VERSION 5.7 ;
BUSBITCHARS "[]" ;
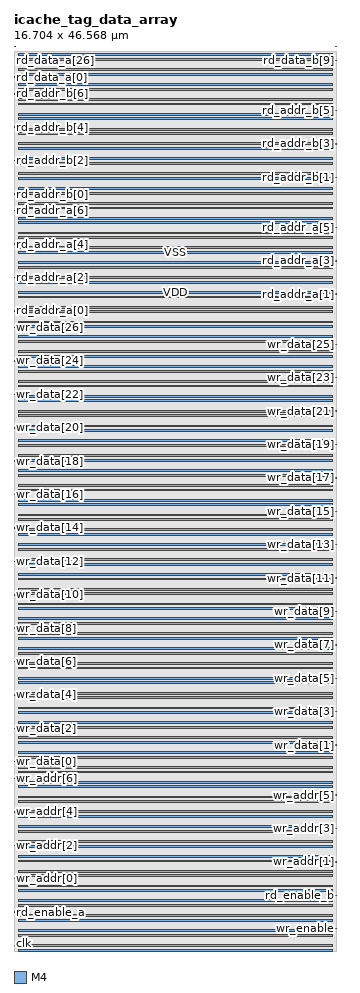
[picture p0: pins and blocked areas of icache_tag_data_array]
MACRO icache_tag_data_array
  FOREIGN icache_tag_data_array 0 0 ;
  SYMMETRY X Y R90 ;
  SIZE 16.704 BY 46.568 ;
  CLASS BLOCK ;
  PIN clk
    DIRECTION INPUT ;
    USE SIGNAL ;
    SHAPE ABUTMENT ;
    PORT
      LAYER M4 ;
      RECT 0.000 0.276 0.072 0.300 ;
    END
  END clk
  PIN wr_enable
    DIRECTION INPUT ;
    USE SIGNAL ;
    SHAPE ABUTMENT ;
    PORT
      LAYER M4 ;
      RECT 16.632 1.140 16.704 1.164 ;
    END
  END wr_enable
  PIN rd_enable_a
    DIRECTION INPUT ;
    USE SIGNAL ;
    SHAPE ABUTMENT ;
    PORT
      LAYER M4 ;
      RECT 0.000 2.004 0.072 2.028 ;
    END
  END rd_enable_a
  PIN rd_enable_b
    DIRECTION INPUT ;
    USE SIGNAL ;
    SHAPE ABUTMENT ;
    PORT
      LAYER M4 ;
      RECT 16.632 2.868 16.704 2.892 ;
    END
  END rd_enable_b
  PIN wr_addr[0]
    DIRECTION INPUT ;
    USE SIGNAL ;
    SHAPE ABUTMENT ;
    PORT
      LAYER M4 ;
      RECT 0.000 3.732 0.072 3.756 ;
    END
  END wr_addr[0]
  PIN wr_addr[1]
    DIRECTION INPUT ;
    USE SIGNAL ;
    SHAPE ABUTMENT ;
    PORT
      LAYER M4 ;
      RECT 16.632 4.596 16.704 4.620 ;
    END
  END wr_addr[1]
  PIN wr_addr[2]
    DIRECTION INPUT ;
    USE SIGNAL ;
    SHAPE ABUTMENT ;
    PORT
      LAYER M4 ;
      RECT 0.000 5.460 0.072 5.484 ;
    END
  END wr_addr[2]
  PIN wr_addr[3]
    DIRECTION INPUT ;
    USE SIGNAL ;
    SHAPE ABUTMENT ;
    PORT
      LAYER M4 ;
      RECT 16.632 6.324 16.704 6.348 ;
    END
  END wr_addr[3]
  PIN wr_addr[4]
    DIRECTION INPUT ;
    USE SIGNAL ;
    SHAPE ABUTMENT ;
    PORT
      LAYER M4 ;
      RECT 0.000 7.188 0.072 7.212 ;
    END
  END wr_addr[4]
  PIN wr_addr[5]
    DIRECTION INPUT ;
    USE SIGNAL ;
    SHAPE ABUTMENT ;
    PORT
      LAYER M4 ;
      RECT 16.632 8.052 16.704 8.076 ;
    END
  END wr_addr[5]
  PIN wr_addr[6]
    DIRECTION INPUT ;
    USE SIGNAL ;
    SHAPE ABUTMENT ;
    PORT
      LAYER M4 ;
      RECT 0.000 8.916 0.072 8.940 ;
    END
  END wr_addr[6]
  PIN wr_data[0]
    DIRECTION INPUT ;
    USE SIGNAL ;
    SHAPE ABUTMENT ;
    PORT
      LAYER M4 ;
      RECT 0.000 9.780 0.072 9.804 ;
    END
  END wr_data[0]
  PIN wr_data[1]
    DIRECTION INPUT ;
    USE SIGNAL ;
    SHAPE ABUTMENT ;
    PORT
      LAYER M4 ;
      RECT 16.632 10.644 16.704 10.668 ;
    END
  END wr_data[1]
  PIN wr_data[2]
    DIRECTION INPUT ;
    USE SIGNAL ;
    SHAPE ABUTMENT ;
    PORT
      LAYER M4 ;
      RECT 0.000 11.508 0.072 11.532 ;
    END
  END wr_data[2]
  PIN wr_data[3]
    DIRECTION INPUT ;
    USE SIGNAL ;
    SHAPE ABUTMENT ;
    PORT
      LAYER M4 ;
      RECT 16.632 12.372 16.704 12.396 ;
    END
  END wr_data[3]
  PIN wr_data[4]
    DIRECTION INPUT ;
    USE SIGNAL ;
    SHAPE ABUTMENT ;
    PORT
      LAYER M4 ;
      RECT 0.000 13.236 0.072 13.260 ;
    END
  END wr_data[4]
  PIN wr_data[5]
    DIRECTION INPUT ;
    USE SIGNAL ;
    SHAPE ABUTMENT ;
    PORT
      LAYER M4 ;
      RECT 16.632 14.100 16.704 14.124 ;
    END
  END wr_data[5]
  PIN wr_data[6]
    DIRECTION INPUT ;
    USE SIGNAL ;
    SHAPE ABUTMENT ;
    PORT
      LAYER M4 ;
      RECT 0.000 14.964 0.072 14.988 ;
    END
  END wr_data[6]
  PIN wr_data[7]
    DIRECTION INPUT ;
    USE SIGNAL ;
    SHAPE ABUTMENT ;
    PORT
      LAYER M4 ;
      RECT 16.632 15.828 16.704 15.852 ;
    END
  END wr_data[7]
  PIN wr_data[8]
    DIRECTION INPUT ;
    USE SIGNAL ;
    SHAPE ABUTMENT ;
    PORT
      LAYER M4 ;
      RECT 0.000 16.692 0.072 16.716 ;
    END
  END wr_data[8]
  PIN wr_data[9]
    DIRECTION INPUT ;
    USE SIGNAL ;
    SHAPE ABUTMENT ;
    PORT
      LAYER M4 ;
      RECT 16.632 17.556 16.704 17.580 ;
    END
  END wr_data[9]
  PIN wr_data[10]
    DIRECTION INPUT ;
    USE SIGNAL ;
    SHAPE ABUTMENT ;
    PORT
      LAYER M4 ;
      RECT 0.000 18.420 0.072 18.444 ;
    END
  END wr_data[10]
  PIN wr_data[11]
    DIRECTION INPUT ;
    USE SIGNAL ;
    SHAPE ABUTMENT ;
    PORT
      LAYER M4 ;
      RECT 16.632 19.284 16.704 19.308 ;
    END
  END wr_data[11]
  PIN wr_data[12]
    DIRECTION INPUT ;
    USE SIGNAL ;
    SHAPE ABUTMENT ;
    PORT
      LAYER M4 ;
      RECT 0.000 20.148 0.072 20.172 ;
    END
  END wr_data[12]
  PIN wr_data[13]
    DIRECTION INPUT ;
    USE SIGNAL ;
    SHAPE ABUTMENT ;
    PORT
      LAYER M4 ;
      RECT 16.632 21.012 16.704 21.036 ;
    END
  END wr_data[13]
  PIN wr_data[14]
    DIRECTION INPUT ;
    USE SIGNAL ;
    SHAPE ABUTMENT ;
    PORT
      LAYER M4 ;
      RECT 0.000 21.876 0.072 21.900 ;
    END
  END wr_data[14]
  PIN wr_data[15]
    DIRECTION INPUT ;
    USE SIGNAL ;
    SHAPE ABUTMENT ;
    PORT
      LAYER M4 ;
      RECT 16.632 22.740 16.704 22.764 ;
    END
  END wr_data[15]
  PIN wr_data[16]
    DIRECTION INPUT ;
    USE SIGNAL ;
    SHAPE ABUTMENT ;
    PORT
      LAYER M4 ;
      RECT 0.000 23.604 0.072 23.628 ;
    END
  END wr_data[16]
  PIN wr_data[17]
    DIRECTION INPUT ;
    USE SIGNAL ;
    SHAPE ABUTMENT ;
    PORT
      LAYER M4 ;
      RECT 16.632 24.468 16.704 24.492 ;
    END
  END wr_data[17]
  PIN wr_data[18]
    DIRECTION INPUT ;
    USE SIGNAL ;
    SHAPE ABUTMENT ;
    PORT
      LAYER M4 ;
      RECT 0.000 25.332 0.072 25.356 ;
    END
  END wr_data[18]
  PIN wr_data[19]
    DIRECTION INPUT ;
    USE SIGNAL ;
    SHAPE ABUTMENT ;
    PORT
      LAYER M4 ;
      RECT 16.632 26.196 16.704 26.220 ;
    END
  END wr_data[19]
  PIN wr_data[20]
    DIRECTION INPUT ;
    USE SIGNAL ;
    SHAPE ABUTMENT ;
    PORT
      LAYER M4 ;
      RECT 0.000 27.060 0.072 27.084 ;
    END
  END wr_data[20]
  PIN wr_data[21]
    DIRECTION INPUT ;
    USE SIGNAL ;
    SHAPE ABUTMENT ;
    PORT
      LAYER M4 ;
      RECT 16.632 27.924 16.704 27.948 ;
    END
  END wr_data[21]
  PIN wr_data[22]
    DIRECTION INPUT ;
    USE SIGNAL ;
    SHAPE ABUTMENT ;
    PORT
      LAYER M4 ;
      RECT 0.000 28.788 0.072 28.812 ;
    END
  END wr_data[22]
  PIN wr_data[23]
    DIRECTION INPUT ;
    USE SIGNAL ;
    SHAPE ABUTMENT ;
    PORT
      LAYER M4 ;
      RECT 16.632 29.652 16.704 29.676 ;
    END
  END wr_data[23]
  PIN wr_data[24]
    DIRECTION INPUT ;
    USE SIGNAL ;
    SHAPE ABUTMENT ;
    PORT
      LAYER M4 ;
      RECT 0.000 30.516 0.072 30.540 ;
    END
  END wr_data[24]
  PIN wr_data[25]
    DIRECTION INPUT ;
    USE SIGNAL ;
    SHAPE ABUTMENT ;
    PORT
      LAYER M4 ;
      RECT 16.632 31.380 16.704 31.404 ;
    END
  END wr_data[25]
  PIN wr_data[26]
    DIRECTION INPUT ;
    USE SIGNAL ;
    SHAPE ABUTMENT ;
    PORT
      LAYER M4 ;
      RECT 0.000 32.244 0.072 32.268 ;
    END
  END wr_data[26]
  PIN rd_addr_a[0]
    DIRECTION INPUT ;
    USE SIGNAL ;
    SHAPE ABUTMENT ;
    PORT
      LAYER M4 ;
      RECT 0.000 33.108 0.072 33.132 ;
    END
  END rd_addr_a[0]
  PIN rd_addr_a[1]
    DIRECTION INPUT ;
    USE SIGNAL ;
    SHAPE ABUTMENT ;
    PORT
      LAYER M4 ;
      RECT 16.632 33.972 16.704 33.996 ;
    END
  END rd_addr_a[1]
  PIN rd_addr_a[2]
    DIRECTION INPUT ;
    USE SIGNAL ;
    SHAPE ABUTMENT ;
    PORT
      LAYER M4 ;
      RECT 0.000 34.836 0.072 34.860 ;
    END
  END rd_addr_a[2]
  PIN rd_addr_a[3]
    DIRECTION INPUT ;
    USE SIGNAL ;
    SHAPE ABUTMENT ;
    PORT
      LAYER M4 ;
      RECT 16.632 35.700 16.704 35.724 ;
    END
  END rd_addr_a[3]
  PIN rd_addr_a[4]
    DIRECTION INPUT ;
    USE SIGNAL ;
    SHAPE ABUTMENT ;
    PORT
      LAYER M4 ;
      RECT 0.000 36.564 0.072 36.588 ;
    END
  END rd_addr_a[4]
  PIN rd_addr_a[5]
    DIRECTION INPUT ;
    USE SIGNAL ;
    SHAPE ABUTMENT ;
    PORT
      LAYER M4 ;
      RECT 16.632 37.428 16.704 37.452 ;
    END
  END rd_addr_a[5]
  PIN rd_addr_a[6]
    DIRECTION INPUT ;
    USE SIGNAL ;
    SHAPE ABUTMENT ;
    PORT
      LAYER M4 ;
      RECT 0.000 38.292 0.072 38.316 ;
    END
  END rd_addr_a[6]
  PIN rd_addr_b[0]
    DIRECTION INPUT ;
    USE SIGNAL ;
    SHAPE ABUTMENT ;
    PORT
      LAYER M4 ;
      RECT 0.000 39.156 0.072 39.180 ;
    END
  END rd_addr_b[0]
  PIN rd_addr_b[1]
    DIRECTION INPUT ;
    USE SIGNAL ;
    SHAPE ABUTMENT ;
    PORT
      LAYER M4 ;
      RECT 16.632 40.020 16.704 40.044 ;
    END
  END rd_addr_b[1]
  PIN rd_addr_b[2]
    DIRECTION INPUT ;
    USE SIGNAL ;
    SHAPE ABUTMENT ;
    PORT
      LAYER M4 ;
      RECT 0.000 40.884 0.072 40.908 ;
    END
  END rd_addr_b[2]
  PIN rd_addr_b[3]
    DIRECTION INPUT ;
    USE SIGNAL ;
    SHAPE ABUTMENT ;
    PORT
      LAYER M4 ;
      RECT 16.632 41.748 16.704 41.772 ;
    END
  END rd_addr_b[3]
  PIN rd_addr_b[4]
    DIRECTION INPUT ;
    USE SIGNAL ;
    SHAPE ABUTMENT ;
    PORT
      LAYER M4 ;
      RECT 0.000 42.612 0.072 42.636 ;
    END
  END rd_addr_b[4]
  PIN rd_addr_b[5]
    DIRECTION INPUT ;
    USE SIGNAL ;
    SHAPE ABUTMENT ;
    PORT
      LAYER M4 ;
      RECT 16.632 43.476 16.704 43.500 ;
    END
  END rd_addr_b[5]
  PIN rd_addr_b[6]
    DIRECTION INPUT ;
    USE SIGNAL ;
    SHAPE ABUTMENT ;
    PORT
      LAYER M4 ;
      RECT 0.000 44.340 0.072 44.364 ;
    END
  END rd_addr_b[6]
  PIN rd_data_a[0]
    DIRECTION OUTPUT ;
    USE SIGNAL ;
    SHAPE ABUTMENT ;
    PORT
      LAYER M4 ;
      RECT 0.000 45.204 0.072 45.228 ;
    END
  END rd_data_a[0]
  PIN rd_data_a[1]
    DIRECTION OUTPUT ;
    USE SIGNAL ;
    SHAPE ABUTMENT ;
    PORT
      LAYER M4 ;
      RECT 16.632 46.068 16.704 46.092 ;
    END
  END rd_data_a[1]
  PIN rd_data_a[2]
    DIRECTION OUTPUT ;
    USE SIGNAL ;
    SHAPE ABUTMENT ;
    PORT
      LAYER M4 ;
      RECT 0.000 46.932 0.072 46.956 ;
    END
  END rd_data_a[2]
  PIN rd_data_a[3]
    DIRECTION OUTPUT ;
    USE SIGNAL ;
    SHAPE ABUTMENT ;
    PORT
      LAYER M4 ;
      RECT 16.632 47.796 16.704 47.820 ;
    END
  END rd_data_a[3]
  PIN rd_data_a[4]
    DIRECTION OUTPUT ;
    USE SIGNAL ;
    SHAPE ABUTMENT ;
    PORT
      LAYER M4 ;
      RECT 0.000 48.660 0.072 48.684 ;
    END
  END rd_data_a[4]
  PIN rd_data_a[5]
    DIRECTION OUTPUT ;
    USE SIGNAL ;
    SHAPE ABUTMENT ;
    PORT
      LAYER M4 ;
      RECT 16.632 49.524 16.704 49.548 ;
    END
  END rd_data_a[5]
  PIN rd_data_a[6]
    DIRECTION OUTPUT ;
    USE SIGNAL ;
    SHAPE ABUTMENT ;
    PORT
      LAYER M4 ;
      RECT 0.000 50.388 0.072 50.412 ;
    END
  END rd_data_a[6]
  PIN rd_data_a[7]
    DIRECTION OUTPUT ;
    USE SIGNAL ;
    SHAPE ABUTMENT ;
    PORT
      LAYER M4 ;
      RECT 16.632 51.252 16.704 51.276 ;
    END
  END rd_data_a[7]
  PIN rd_data_a[8]
    DIRECTION OUTPUT ;
    USE SIGNAL ;
    SHAPE ABUTMENT ;
    PORT
      LAYER M4 ;
      RECT 0.000 52.116 0.072 52.140 ;
    END
  END rd_data_a[8]
  PIN rd_data_a[9]
    DIRECTION OUTPUT ;
    USE SIGNAL ;
    SHAPE ABUTMENT ;
    PORT
      LAYER M4 ;
      RECT 16.632 52.980 16.704 53.004 ;
    END
  END rd_data_a[9]
  PIN rd_data_a[10]
    DIRECTION OUTPUT ;
    USE SIGNAL ;
    SHAPE ABUTMENT ;
    PORT
      LAYER M4 ;
      RECT 0.000 53.844 0.072 53.868 ;
    END
  END rd_data_a[10]
  PIN rd_data_a[11]
    DIRECTION OUTPUT ;
    USE SIGNAL ;
    SHAPE ABUTMENT ;
    PORT
      LAYER M4 ;
      RECT 16.632 54.708 16.704 54.732 ;
    END
  END rd_data_a[11]
  PIN rd_data_a[12]
    DIRECTION OUTPUT ;
    USE SIGNAL ;
    SHAPE ABUTMENT ;
    PORT
      LAYER M4 ;
      RECT 0.000 55.572 0.072 55.596 ;
    END
  END rd_data_a[12]
  PIN rd_data_a[13]
    DIRECTION OUTPUT ;
    USE SIGNAL ;
    SHAPE ABUTMENT ;
    PORT
      LAYER M4 ;
      RECT 16.632 56.436 16.704 56.460 ;
    END
  END rd_data_a[13]
  PIN rd_data_a[14]
    DIRECTION OUTPUT ;
    USE SIGNAL ;
    SHAPE ABUTMENT ;
    PORT
      LAYER M4 ;
      RECT 0.000 57.300 0.072 57.324 ;
    END
  END rd_data_a[14]
  PIN rd_data_a[15]
    DIRECTION OUTPUT ;
    USE SIGNAL ;
    SHAPE ABUTMENT ;
    PORT
      LAYER M4 ;
      RECT 16.632 58.164 16.704 58.188 ;
    END
  END rd_data_a[15]
  PIN rd_data_a[16]
    DIRECTION OUTPUT ;
    USE SIGNAL ;
    SHAPE ABUTMENT ;
    PORT
      LAYER M4 ;
      RECT 0.000 59.028 0.072 59.052 ;
    END
  END rd_data_a[16]
  PIN rd_data_a[17]
    DIRECTION OUTPUT ;
    USE SIGNAL ;
    SHAPE ABUTMENT ;
    PORT
      LAYER M4 ;
      RECT 16.632 59.892 16.704 59.916 ;
    END
  END rd_data_a[17]
  PIN rd_data_a[18]
    DIRECTION OUTPUT ;
    USE SIGNAL ;
    SHAPE ABUTMENT ;
    PORT
      LAYER M4 ;
      RECT 0.000 60.756 0.072 60.780 ;
    END
  END rd_data_a[18]
  PIN rd_data_a[19]
    DIRECTION OUTPUT ;
    USE SIGNAL ;
    SHAPE ABUTMENT ;
    PORT
      LAYER M4 ;
      RECT 16.632 61.620 16.704 61.644 ;
    END
  END rd_data_a[19]
  PIN rd_data_a[20]
    DIRECTION OUTPUT ;
    USE SIGNAL ;
    SHAPE ABUTMENT ;
    PORT
      LAYER M4 ;
      RECT 0.000 62.484 0.072 62.508 ;
    END
  END rd_data_a[20]
  PIN rd_data_a[21]
    DIRECTION OUTPUT ;
    USE SIGNAL ;
    SHAPE ABUTMENT ;
    PORT
      LAYER M4 ;
      RECT 16.632 63.348 16.704 63.372 ;
    END
  END rd_data_a[21]
  PIN rd_data_a[22]
    DIRECTION OUTPUT ;
    USE SIGNAL ;
    SHAPE ABUTMENT ;
    PORT
      LAYER M4 ;
      RECT 0.000 64.212 0.072 64.236 ;
    END
  END rd_data_a[22]
  PIN rd_data_a[23]
    DIRECTION OUTPUT ;
    USE SIGNAL ;
    SHAPE ABUTMENT ;
    PORT
      LAYER M4 ;
      RECT 16.632 65.076 16.704 65.100 ;
    END
  END rd_data_a[23]
  PIN rd_data_a[24]
    DIRECTION OUTPUT ;
    USE SIGNAL ;
    SHAPE ABUTMENT ;
    PORT
      LAYER M4 ;
      RECT 0.000 65.940 0.072 65.964 ;
    END
  END rd_data_a[24]
  PIN rd_data_a[25]
    DIRECTION OUTPUT ;
    USE SIGNAL ;
    SHAPE ABUTMENT ;
    PORT
      LAYER M4 ;
      RECT 16.632 66.804 16.704 66.828 ;
    END
  END rd_data_a[25]
  PIN rd_data_a[26]
    DIRECTION OUTPUT ;
    USE SIGNAL ;
    SHAPE ABUTMENT ;
    PORT
      LAYER M4 ;
      RECT 0.000 67.668 0.072 67.692 ;
    END
  END rd_data_a[26]
  PIN rd_data_b[0]
    DIRECTION OUTPUT ;
    USE SIGNAL ;
    SHAPE ABUTMENT ;
    PORT
      LAYER M4 ;
      RECT 0.000 68.532 0.072 68.556 ;
    END
  END rd_data_b[0]
  PIN rd_data_b[1]
    DIRECTION OUTPUT ;
    USE SIGNAL ;
    SHAPE ABUTMENT ;
    PORT
      LAYER M4 ;
      RECT 16.632 69.396 16.704 69.420 ;
    END
  END rd_data_b[1]
  PIN rd_data_b[2]
    DIRECTION OUTPUT ;
    USE SIGNAL ;
    SHAPE ABUTMENT ;
    PORT
      LAYER M4 ;
      RECT 0.000 70.260 0.072 70.284 ;
    END
  END rd_data_b[2]
  PIN rd_data_b[3]
    DIRECTION OUTPUT ;
    USE SIGNAL ;
    SHAPE ABUTMENT ;
    PORT
      LAYER M4 ;
      RECT 16.632 71.124 16.704 71.148 ;
    END
  END rd_data_b[3]
  PIN rd_data_b[4]
    DIRECTION OUTPUT ;
    USE SIGNAL ;
    SHAPE ABUTMENT ;
    PORT
      LAYER M4 ;
      RECT 0.000 71.988 0.072 72.012 ;
    END
  END rd_data_b[4]
  PIN rd_data_b[5]
    DIRECTION OUTPUT ;
    USE SIGNAL ;
    SHAPE ABUTMENT ;
    PORT
      LAYER M4 ;
      RECT 16.632 72.852 16.704 72.876 ;
    END
  END rd_data_b[5]
  PIN rd_data_b[6]
    DIRECTION OUTPUT ;
    USE SIGNAL ;
    SHAPE ABUTMENT ;
    PORT
      LAYER M4 ;
      RECT 0.000 73.716 0.072 73.740 ;
    END
  END rd_data_b[6]
  PIN rd_data_b[7]
    DIRECTION OUTPUT ;
    USE SIGNAL ;
    SHAPE ABUTMENT ;
    PORT
      LAYER M4 ;
      RECT 16.632 74.580 16.704 74.604 ;
    END
  END rd_data_b[7]
  PIN rd_data_b[8]
    DIRECTION OUTPUT ;
    USE SIGNAL ;
    SHAPE ABUTMENT ;
    PORT
      LAYER M4 ;
      RECT 0.000 75.444 0.072 75.468 ;
    END
  END rd_data_b[8]
  PIN rd_data_b[9]
    DIRECTION OUTPUT ;
    USE SIGNAL ;
    SHAPE ABUTMENT ;
    PORT
      LAYER M4 ;
      RECT 16.632 76.308 16.704 76.332 ;
    END
  END rd_data_b[9]
  PIN rd_data_b[10]
    DIRECTION OUTPUT ;
    USE SIGNAL ;
    SHAPE ABUTMENT ;
    PORT
      LAYER M4 ;
      RECT 0.000 77.172 0.072 77.196 ;
    END
  END rd_data_b[10]
  PIN rd_data_b[11]
    DIRECTION OUTPUT ;
    USE SIGNAL ;
    SHAPE ABUTMENT ;
    PORT
      LAYER M4 ;
      RECT 16.632 78.036 16.704 78.060 ;
    END
  END rd_data_b[11]
  PIN rd_data_b[12]
    DIRECTION OUTPUT ;
    USE SIGNAL ;
    SHAPE ABUTMENT ;
    PORT
      LAYER M4 ;
      RECT 0.000 78.900 0.072 78.924 ;
    END
  END rd_data_b[12]
  PIN rd_data_b[13]
    DIRECTION OUTPUT ;
    USE SIGNAL ;
    SHAPE ABUTMENT ;
    PORT
      LAYER M4 ;
      RECT 16.632 79.764 16.704 79.788 ;
    END
  END rd_data_b[13]
  PIN rd_data_b[14]
    DIRECTION OUTPUT ;
    USE SIGNAL ;
    SHAPE ABUTMENT ;
    PORT
      LAYER M4 ;
      RECT 0.000 80.628 0.072 80.652 ;
    END
  END rd_data_b[14]
  PIN rd_data_b[15]
    DIRECTION OUTPUT ;
    USE SIGNAL ;
    SHAPE ABUTMENT ;
    PORT
      LAYER M4 ;
      RECT 16.632 81.492 16.704 81.516 ;
    END
  END rd_data_b[15]
  PIN rd_data_b[16]
    DIRECTION OUTPUT ;
    USE SIGNAL ;
    SHAPE ABUTMENT ;
    PORT
      LAYER M4 ;
      RECT 0.000 82.356 0.072 82.380 ;
    END
  END rd_data_b[16]
  PIN rd_data_b[17]
    DIRECTION OUTPUT ;
    USE SIGNAL ;
    SHAPE ABUTMENT ;
    PORT
      LAYER M4 ;
      RECT 16.632 83.220 16.704 83.244 ;
    END
  END rd_data_b[17]
  PIN rd_data_b[18]
    DIRECTION OUTPUT ;
    USE SIGNAL ;
    SHAPE ABUTMENT ;
    PORT
      LAYER M4 ;
      RECT 0.000 84.084 0.072 84.108 ;
    END
  END rd_data_b[18]
  PIN rd_data_b[19]
    DIRECTION OUTPUT ;
    USE SIGNAL ;
    SHAPE ABUTMENT ;
    PORT
      LAYER M4 ;
      RECT 16.632 84.948 16.704 84.972 ;
    END
  END rd_data_b[19]
  PIN rd_data_b[20]
    DIRECTION OUTPUT ;
    USE SIGNAL ;
    SHAPE ABUTMENT ;
    PORT
      LAYER M4 ;
      RECT 0.000 85.812 0.072 85.836 ;
    END
  END rd_data_b[20]
  PIN rd_data_b[21]
    DIRECTION OUTPUT ;
    USE SIGNAL ;
    SHAPE ABUTMENT ;
    PORT
      LAYER M4 ;
      RECT 16.632 86.676 16.704 86.700 ;
    END
  END rd_data_b[21]
  PIN rd_data_b[22]
    DIRECTION OUTPUT ;
    USE SIGNAL ;
    SHAPE ABUTMENT ;
    PORT
      LAYER M4 ;
      RECT 0.000 87.540 0.072 87.564 ;
    END
  END rd_data_b[22]
  PIN rd_data_b[23]
    DIRECTION OUTPUT ;
    USE SIGNAL ;
    SHAPE ABUTMENT ;
    PORT
      LAYER M4 ;
      RECT 16.632 88.404 16.704 88.428 ;
    END
  END rd_data_b[23]
  PIN rd_data_b[24]
    DIRECTION OUTPUT ;
    USE SIGNAL ;
    SHAPE ABUTMENT ;
    PORT
      LAYER M4 ;
      RECT 0.000 89.268 0.072 89.292 ;
    END
  END rd_data_b[24]
  PIN rd_data_b[25]
    DIRECTION OUTPUT ;
    USE SIGNAL ;
    SHAPE ABUTMENT ;
    PORT
      LAYER M4 ;
      RECT 16.632 90.132 16.704 90.156 ;
    END
  END rd_data_b[25]
  PIN rd_data_b[26]
    DIRECTION OUTPUT ;
    USE SIGNAL ;
    SHAPE ABUTMENT ;
    PORT
      LAYER M4 ;
      RECT 0.000 90.996 0.072 91.020 ;
    END
  END rd_data_b[26]
  PIN VSS
    DIRECTION INOUT ;
    USE GROUND ;
    PORT
      LAYER M4 ;
      RECT 0.216 0.000 16.488 0.096 ;
      RECT 0.216 0.768 16.488 0.864 ;
      RECT 0.216 1.536 16.488 1.632 ;
      RECT 0.216 2.304 16.488 2.400 ;
      RECT 0.216 3.072 16.488 3.168 ;
      RECT 0.216 3.840 16.488 3.936 ;
      RECT 0.216 4.608 16.488 4.704 ;
      RECT 0.216 5.376 16.488 5.472 ;
      RECT 0.216 6.144 16.488 6.240 ;
      RECT 0.216 6.912 16.488 7.008 ;
      RECT 0.216 7.680 16.488 7.776 ;
      RECT 0.216 8.448 16.488 8.544 ;
      RECT 0.216 9.216 16.488 9.312 ;
      RECT 0.216 9.984 16.488 10.080 ;
      RECT 0.216 10.752 16.488 10.848 ;
      RECT 0.216 11.520 16.488 11.616 ;
      RECT 0.216 12.288 16.488 12.384 ;
      RECT 0.216 13.056 16.488 13.152 ;
      RECT 0.216 13.824 16.488 13.920 ;
      RECT 0.216 14.592 16.488 14.688 ;
      RECT 0.216 15.360 16.488 15.456 ;
      RECT 0.216 16.128 16.488 16.224 ;
      RECT 0.216 16.896 16.488 16.992 ;
      RECT 0.216 17.664 16.488 17.760 ;
      RECT 0.216 18.432 16.488 18.528 ;
      RECT 0.216 19.200 16.488 19.296 ;
      RECT 0.216 19.968 16.488 20.064 ;
      RECT 0.216 20.736 16.488 20.832 ;
      RECT 0.216 21.504 16.488 21.600 ;
      RECT 0.216 22.272 16.488 22.368 ;
      RECT 0.216 23.040 16.488 23.136 ;
      RECT 0.216 23.808 16.488 23.904 ;
      RECT 0.216 24.576 16.488 24.672 ;
      RECT 0.216 25.344 16.488 25.440 ;
      RECT 0.216 26.112 16.488 26.208 ;
      RECT 0.216 26.880 16.488 26.976 ;
      RECT 0.216 27.648 16.488 27.744 ;
      RECT 0.216 28.416 16.488 28.512 ;
      RECT 0.216 29.184 16.488 29.280 ;
      RECT 0.216 29.952 16.488 30.048 ;
      RECT 0.216 30.720 16.488 30.816 ;
      RECT 0.216 31.488 16.488 31.584 ;
      RECT 0.216 32.256 16.488 32.352 ;
      RECT 0.216 33.024 16.488 33.120 ;
      RECT 0.216 33.792 16.488 33.888 ;
      RECT 0.216 34.560 16.488 34.656 ;
      RECT 0.216 35.328 16.488 35.424 ;
      RECT 0.216 36.096 16.488 36.192 ;
      RECT 0.216 36.864 16.488 36.960 ;
      RECT 0.216 37.632 16.488 37.728 ;
      RECT 0.216 38.400 16.488 38.496 ;
      RECT 0.216 39.168 16.488 39.264 ;
      RECT 0.216 39.936 16.488 40.032 ;
      RECT 0.216 40.704 16.488 40.800 ;
      RECT 0.216 41.472 16.488 41.568 ;
      RECT 0.216 42.240 16.488 42.336 ;
      RECT 0.216 43.008 16.488 43.104 ;
      RECT 0.216 43.776 16.488 43.872 ;
      RECT 0.216 44.544 16.488 44.640 ;
      RECT 0.216 45.312 16.488 45.408 ;
      RECT 0.216 46.080 16.488 46.176 ;
    END
  END VSS
  PIN VDD
    DIRECTION INOUT ;
    USE POWER ;
    PORT
      LAYER M4 ;
      RECT 0.216 0.240 16.488 0.336 ;
      RECT 0.216 1.008 16.488 1.104 ;
      RECT 0.216 1.776 16.488 1.872 ;
      RECT 0.216 2.544 16.488 2.640 ;
      RECT 0.216 3.312 16.488 3.408 ;
      RECT 0.216 4.080 16.488 4.176 ;
      RECT 0.216 4.848 16.488 4.944 ;
      RECT 0.216 5.616 16.488 5.712 ;
      RECT 0.216 6.384 16.488 6.480 ;
      RECT 0.216 7.152 16.488 7.248 ;
      RECT 0.216 7.920 16.488 8.016 ;
      RECT 0.216 8.688 16.488 8.784 ;
      RECT 0.216 9.456 16.488 9.552 ;
      RECT 0.216 10.224 16.488 10.320 ;
      RECT 0.216 10.992 16.488 11.088 ;
      RECT 0.216 11.760 16.488 11.856 ;
      RECT 0.216 12.528 16.488 12.624 ;
      RECT 0.216 13.296 16.488 13.392 ;
      RECT 0.216 14.064 16.488 14.160 ;
      RECT 0.216 14.832 16.488 14.928 ;
      RECT 0.216 15.600 16.488 15.696 ;
      RECT 0.216 16.368 16.488 16.464 ;
      RECT 0.216 17.136 16.488 17.232 ;
      RECT 0.216 17.904 16.488 18.000 ;
      RECT 0.216 18.672 16.488 18.768 ;
      RECT 0.216 19.440 16.488 19.536 ;
      RECT 0.216 20.208 16.488 20.304 ;
      RECT 0.216 20.976 16.488 21.072 ;
      RECT 0.216 21.744 16.488 21.840 ;
      RECT 0.216 22.512 16.488 22.608 ;
      RECT 0.216 23.280 16.488 23.376 ;
      RECT 0.216 24.048 16.488 24.144 ;
      RECT 0.216 24.816 16.488 24.912 ;
      RECT 0.216 25.584 16.488 25.680 ;
      RECT 0.216 26.352 16.488 26.448 ;
      RECT 0.216 27.120 16.488 27.216 ;
      RECT 0.216 27.888 16.488 27.984 ;
      RECT 0.216 28.656 16.488 28.752 ;
      RECT 0.216 29.424 16.488 29.520 ;
      RECT 0.216 30.192 16.488 30.288 ;
      RECT 0.216 30.960 16.488 31.056 ;
      RECT 0.216 31.728 16.488 31.824 ;
      RECT 0.216 32.496 16.488 32.592 ;
      RECT 0.216 33.264 16.488 33.360 ;
      RECT 0.216 34.032 16.488 34.128 ;
      RECT 0.216 34.800 16.488 34.896 ;
      RECT 0.216 35.568 16.488 35.664 ;
      RECT 0.216 36.336 16.488 36.432 ;
      RECT 0.216 37.104 16.488 37.200 ;
      RECT 0.216 37.872 16.488 37.968 ;
      RECT 0.216 38.640 16.488 38.736 ;
      RECT 0.216 39.408 16.488 39.504 ;
      RECT 0.216 40.176 16.488 40.272 ;
      RECT 0.216 40.944 16.488 41.040 ;
      RECT 0.216 41.712 16.488 41.808 ;
      RECT 0.216 42.480 16.488 42.576 ;
      RECT 0.216 43.248 16.488 43.344 ;
      RECT 0.216 44.016 16.488 44.112 ;
      RECT 0.216 44.784 16.488 44.880 ;
      RECT 0.216 45.552 16.488 45.648 ;
      RECT 0.216 46.320 16.488 46.416 ;
    END
  END VDD
  OBS
    LAYER M1 ;
    RECT 0 0 16.704 46.568 ;
    LAYER M2 ;
    RECT 0 0 16.704 46.568 ;
    LAYER M3 ;
    RECT 0 0 16.704 46.568 ;
    LAYER M4 ;
    RECT 0 0 16.704 46.568 ;
  END
END icache_tag_data_array

END LIBRARY
